VERSION 5.7 ;
  NOWIREEXTENSIONATPIN ON ;
  DIVIDERCHAR "/" ;
  BUSBITCHARS "[]" ;
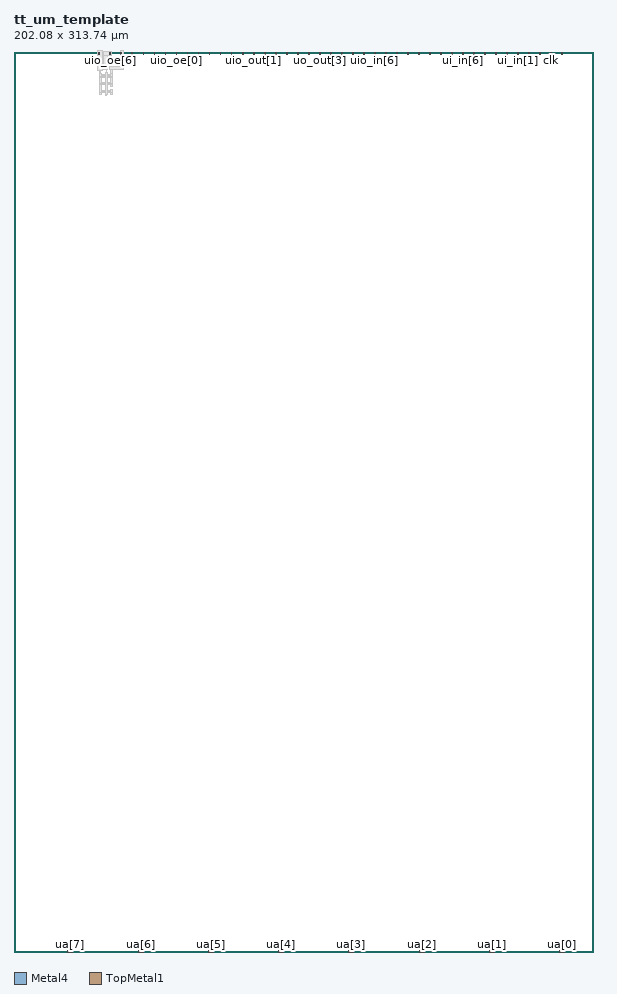
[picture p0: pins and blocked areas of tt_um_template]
MACRO tt_um_template
  CLASS BLOCK ;
  FOREIGN tt_um_template ;
  ORIGIN 0.000 0.000 ;
  SIZE 202.080 BY 313.740 ;
  PIN clk
    DIRECTION INPUT ;
    USE SIGNAL ;
    PORT
      LAYER Metal4 ;
        RECT 187.050 312.740 187.350 313.740 ;
    END
  END clk
  PIN ena
    DIRECTION INPUT ;
    USE SIGNAL ;
    PORT
      LAYER Metal4 ;
        RECT 190.890 312.740 191.190 313.740 ;
    END
  END ena
  PIN rst_n
    DIRECTION INPUT ;
    USE SIGNAL ;
    PORT
      LAYER Metal4 ;
        RECT 183.210 312.740 183.510 313.740 ;
    END
  END rst_n
  PIN ua[0]
    DIRECTION INOUT ;
    USE SIGNAL ;
    PORT
      LAYER TopMetal1 ;
        RECT 190.165 0.000 191.915 2.000 ;
    END
  END ua[0]
  PIN ua[1]
    DIRECTION INOUT ;
    USE SIGNAL ;
    PORT
      LAYER TopMetal1 ;
        RECT 165.685 0.000 167.435 2.000 ;
    END
  END ua[1]
  PIN ua[2]
    DIRECTION INOUT ;
    USE SIGNAL ;
    PORT
      LAYER TopMetal1 ;
        RECT 141.205 0.000 142.955 2.000 ;
    END
  END ua[2]
  PIN ua[3]
    DIRECTION INOUT ;
    USE SIGNAL ;
    PORT
      LAYER TopMetal1 ;
        RECT 116.725 0.000 118.475 2.000 ;
    END
  END ua[3]
  PIN ua[4]
    DIRECTION INOUT ;
    USE SIGNAL ;
    PORT
      LAYER TopMetal1 ;
        RECT 92.245 0.000 93.995 2.000 ;
    END
  END ua[4]
  PIN ua[5]
    DIRECTION INOUT ;
    USE SIGNAL ;
    PORT
      LAYER TopMetal1 ;
        RECT 67.765 0.000 69.515 2.000 ;
    END
  END ua[5]
  PIN ua[6]
    DIRECTION INOUT ;
    USE SIGNAL ;
    PORT
      LAYER TopMetal1 ;
        RECT 43.285 0.000 45.035 2.000 ;
    END
  END ua[6]
  PIN ua[7]
    DIRECTION INOUT ;
    USE SIGNAL ;
    PORT
      LAYER TopMetal1 ;
        RECT 18.805 0.000 20.555 2.000 ;
    END
  END ua[7]
  PIN ui_in[0]
    DIRECTION INPUT ;
    USE SIGNAL ;
    PORT
      LAYER Metal4 ;
        RECT 179.370 312.740 179.670 313.740 ;
    END
  END ui_in[0]
  PIN ui_in[1]
    DIRECTION INPUT ;
    USE SIGNAL ;
    PORT
      LAYER Metal4 ;
        RECT 175.530 312.740 175.830 313.740 ;
    END
  END ui_in[1]
  PIN ui_in[2]
    DIRECTION INPUT ;
    USE SIGNAL ;
    PORT
      LAYER Metal4 ;
        RECT 171.690 312.740 171.990 313.740 ;
    END
  END ui_in[2]
  PIN ui_in[3]
    DIRECTION INPUT ;
    USE SIGNAL ;
    PORT
      LAYER Metal4 ;
        RECT 167.850 312.740 168.150 313.740 ;
    END
  END ui_in[3]
  PIN ui_in[4]
    DIRECTION INPUT ;
    USE SIGNAL ;
    PORT
      LAYER Metal4 ;
        RECT 164.010 312.740 164.310 313.740 ;
    END
  END ui_in[4]
  PIN ui_in[5]
    DIRECTION INPUT ;
    USE SIGNAL ;
    PORT
      LAYER Metal4 ;
        RECT 160.170 312.740 160.470 313.740 ;
    END
  END ui_in[5]
  PIN ui_in[6]
    DIRECTION INPUT ;
    USE SIGNAL ;
    PORT
      LAYER Metal4 ;
        RECT 156.330 312.740 156.630 313.740 ;
    END
  END ui_in[6]
  PIN ui_in[7]
    DIRECTION INPUT ;
    USE SIGNAL ;
    PORT
      LAYER Metal4 ;
        RECT 152.490 312.740 152.790 313.740 ;
    END
  END ui_in[7]
  PIN uio_in[0]
    DIRECTION INPUT ;
    USE SIGNAL ;
    PORT
      LAYER Metal4 ;
        RECT 148.650 312.740 148.950 313.740 ;
    END
  END uio_in[0]
  PIN uio_in[1]
    DIRECTION INPUT ;
    USE SIGNAL ;
    PORT
      LAYER Metal4 ;
        RECT 144.810 312.740 145.110 313.740 ;
    END
  END uio_in[1]
  PIN uio_in[2]
    DIRECTION INPUT ;
    USE SIGNAL ;
    PORT
      LAYER Metal4 ;
        RECT 140.970 312.740 141.270 313.740 ;
    END
  END uio_in[2]
  PIN uio_in[3]
    DIRECTION INPUT ;
    USE SIGNAL ;
    PORT
      LAYER Metal4 ;
        RECT 137.130 312.740 137.430 313.740 ;
    END
  END uio_in[3]
  PIN uio_in[4]
    DIRECTION INPUT ;
    USE SIGNAL ;
    PORT
      LAYER Metal4 ;
        RECT 133.290 312.740 133.590 313.740 ;
    END
  END uio_in[4]
  PIN uio_in[5]
    DIRECTION INPUT ;
    USE SIGNAL ;
    PORT
      LAYER Metal4 ;
        RECT 129.450 312.740 129.750 313.740 ;
    END
  END uio_in[5]
  PIN uio_in[6]
    DIRECTION INPUT ;
    USE SIGNAL ;
    PORT
      LAYER Metal4 ;
        RECT 125.610 312.740 125.910 313.740 ;
    END
  END uio_in[6]
  PIN uio_in[7]
    DIRECTION INPUT ;
    USE SIGNAL ;
    PORT
      LAYER Metal4 ;
        RECT 121.770 312.740 122.070 313.740 ;
    END
  END uio_in[7]
  PIN uio_oe[0]
    DIRECTION OUTPUT ;
    USE SIGNAL ;
    PORT
      LAYER Metal4 ;
        RECT 56.490 312.740 56.790 313.740 ;
    END
  END uio_oe[0]
  PIN uio_oe[1]
    DIRECTION OUTPUT ;
    USE SIGNAL ;
    PORT
      LAYER Metal4 ;
        RECT 52.650 312.740 52.950 313.740 ;
    END
  END uio_oe[1]
  PIN uio_oe[2]
    DIRECTION OUTPUT ;
    USE SIGNAL ;
    PORT
      LAYER Metal4 ;
        RECT 48.810 312.740 49.110 313.740 ;
    END
  END uio_oe[2]
  PIN uio_oe[3]
    DIRECTION OUTPUT ;
    USE SIGNAL ;
    PORT
      LAYER Metal4 ;
        RECT 44.970 312.740 45.270 313.740 ;
    END
  END uio_oe[3]
  PIN uio_oe[4]
    DIRECTION OUTPUT ;
    USE SIGNAL ;
    PORT
      LAYER Metal4 ;
        RECT 41.130 312.740 41.430 313.740 ;
    END
  END uio_oe[4]
  PIN uio_oe[5]
    DIRECTION OUTPUT ;
    USE SIGNAL ;
    PORT
      LAYER Metal4 ;
        RECT 37.290 312.740 37.590 313.740 ;
    END
  END uio_oe[5]
  PIN uio_oe[6]
    DIRECTION OUTPUT ;
    USE SIGNAL ;
    PORT
      LAYER Metal4 ;
        RECT 33.450 312.740 33.750 313.740 ;
    END
  END uio_oe[6]
  PIN uio_oe[7]
    DIRECTION OUTPUT ;
    USE SIGNAL ;
    PORT
      LAYER Metal4 ;
        RECT 29.610 312.740 29.910 313.740 ;
    END
  END uio_oe[7]
  PIN uio_out[0]
    DIRECTION OUTPUT ;
    USE SIGNAL ;
    PORT
      LAYER Metal4 ;
        RECT 87.210 312.740 87.510 313.740 ;
    END
  END uio_out[0]
  PIN uio_out[1]
    DIRECTION OUTPUT ;
    USE SIGNAL ;
    PORT
      LAYER Metal4 ;
        RECT 83.370 312.740 83.670 313.740 ;
    END
  END uio_out[1]
  PIN uio_out[2]
    DIRECTION OUTPUT ;
    USE SIGNAL ;
    PORT
      LAYER Metal4 ;
        RECT 79.530 312.740 79.830 313.740 ;
    END
  END uio_out[2]
  PIN uio_out[3]
    DIRECTION OUTPUT ;
    USE SIGNAL ;
    PORT
      LAYER Metal4 ;
        RECT 75.690 312.740 75.990 313.740 ;
    END
  END uio_out[3]
  PIN uio_out[4]
    DIRECTION OUTPUT ;
    USE SIGNAL ;
    PORT
      LAYER Metal4 ;
        RECT 71.850 312.740 72.150 313.740 ;
    END
  END uio_out[4]
  PIN uio_out[5]
    DIRECTION OUTPUT ;
    USE SIGNAL ;
    PORT
      LAYER Metal4 ;
        RECT 68.010 312.740 68.310 313.740 ;
    END
  END uio_out[5]
  PIN uio_out[6]
    DIRECTION OUTPUT ;
    USE SIGNAL ;
    PORT
      LAYER Metal4 ;
        RECT 64.170 312.740 64.470 313.740 ;
    END
  END uio_out[6]
  PIN uio_out[7]
    DIRECTION OUTPUT ;
    USE SIGNAL ;
    PORT
      LAYER Metal4 ;
        RECT 60.330 312.740 60.630 313.740 ;
    END
  END uio_out[7]
  PIN uo_out[0]
    DIRECTION OUTPUT ;
    USE SIGNAL ;
    PORT
      LAYER Metal4 ;
        RECT 117.930 312.740 118.230 313.740 ;
    END
  END uo_out[0]
  PIN uo_out[1]
    DIRECTION OUTPUT ;
    USE SIGNAL ;
    PORT
      LAYER Metal4 ;
        RECT 114.090 312.740 114.390 313.740 ;
    END
  END uo_out[1]
  PIN uo_out[2]
    DIRECTION OUTPUT ;
    USE SIGNAL ;
    PORT
      LAYER Metal4 ;
        RECT 110.250 312.740 110.550 313.740 ;
    END
  END uo_out[2]
  PIN uo_out[3]
    DIRECTION OUTPUT ;
    USE SIGNAL ;
    PORT
      LAYER Metal4 ;
        RECT 106.410 312.740 106.710 313.740 ;
    END
  END uo_out[3]
  PIN uo_out[4]
    DIRECTION OUTPUT ;
    USE SIGNAL ;
    PORT
      LAYER Metal4 ;
        RECT 102.570 312.740 102.870 313.740 ;
    END
  END uo_out[4]
  PIN uo_out[5]
    DIRECTION OUTPUT ;
    USE SIGNAL ;
    PORT
      LAYER Metal4 ;
        RECT 98.730 312.740 99.030 313.740 ;
    END
  END uo_out[5]
  PIN uo_out[6]
    DIRECTION OUTPUT ;
    USE SIGNAL ;
    PORT
      LAYER Metal4 ;
        RECT 94.890 312.740 95.190 313.740 ;
    END
  END uo_out[6]
  PIN uo_out[7]
    DIRECTION OUTPUT ;
    USE SIGNAL ;
    PORT
      LAYER Metal4 ;
        RECT 91.050 312.740 91.350 313.740 ;
    END
  END uo_out[7]
  OBS
      LAYER GatPoly ;
        RECT 30.505 305.340 30.685 305.470 ;
        RECT 31.805 305.340 32.550 305.470 ;
        RECT 33.290 305.340 33.470 305.470 ;
        RECT 32.030 305.000 32.360 305.340 ;
        RECT 30.505 302.680 30.685 302.810 ;
        RECT 31.805 302.680 32.550 302.810 ;
        RECT 33.290 302.680 33.470 302.810 ;
        RECT 32.030 302.340 32.360 302.680 ;
        RECT 30.445 299.780 30.625 299.910 ;
        RECT 31.745 299.780 32.490 299.910 ;
        RECT 33.230 299.780 33.410 299.910 ;
        RECT 31.970 299.440 32.300 299.780 ;
      LAYER Metal1 ;
        RECT 28.940 307.440 30.790 314.120 ;
        RECT 31.250 312.580 33.930 314.020 ;
        RECT 31.310 307.540 32.750 312.580 ;
        RECT 37.040 308.770 38.060 314.100 ;
        RECT 33.280 307.560 38.060 308.770 ;
        RECT 29.820 306.360 30.290 307.440 ;
        RECT 29.790 305.280 30.400 306.360 ;
        RECT 32.080 305.775 32.360 307.540 ;
        RECT 33.560 306.360 34.190 307.560 ;
        RECT 30.705 305.545 33.270 305.775 ;
        RECT 32.030 305.310 32.360 305.315 ;
        RECT 29.790 305.020 31.645 305.280 ;
        RECT 29.790 302.620 30.400 305.020 ;
        RECT 32.000 303.115 32.400 305.310 ;
        RECT 33.530 305.280 34.190 306.360 ;
        RECT 32.670 305.020 34.190 305.280 ;
        RECT 30.705 302.885 33.270 303.115 ;
        RECT 32.030 302.640 32.360 302.655 ;
        RECT 29.790 302.360 31.645 302.620 ;
        RECT 29.790 299.720 30.400 302.360 ;
        RECT 32.000 302.340 32.360 302.640 ;
        RECT 33.530 302.620 34.190 305.020 ;
        RECT 32.670 302.360 34.190 302.620 ;
        RECT 32.000 300.215 32.330 302.340 ;
        RECT 33.530 301.590 34.190 302.360 ;
        RECT 30.645 299.985 33.210 300.215 ;
        RECT 29.790 299.460 31.585 299.720 ;
        RECT 29.790 298.900 30.400 299.460 ;
        RECT 31.960 298.690 32.320 299.770 ;
        RECT 33.530 299.720 34.190 300.590 ;
        RECT 32.610 299.460 34.190 299.720 ;
        RECT 33.530 298.850 34.190 299.460 ;
      LAYER Metal2 ;
        RECT 32.000 298.780 32.440 306.620 ;
  END
END tt_um_template
END LIBRARY

